VERSION 5.7 ;
  NOWIREEXTENSIONATPIN ON ;
  DIVIDERCHAR "/" ;
  BUSBITCHARS "[]" ;
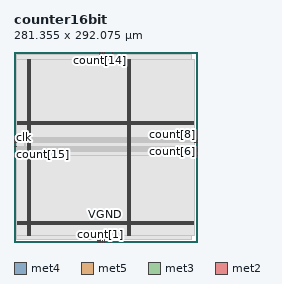
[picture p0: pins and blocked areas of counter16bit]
MACRO counter16bit
  CLASS BLOCK ;
  FOREIGN counter16bit ;
  ORIGIN 0.000 0.000 ;
  SIZE 281.355 BY 292.075 ;
  PIN VGND
    DIRECTION INOUT ;
    USE GROUND ;
    PORT
      LAYER met4 ;
        RECT 24.340 10.640 25.940 280.400 ;
    END
    PORT
      LAYER met4 ;
        RECT 177.940 10.640 179.540 280.400 ;
    END
    PORT
      LAYER met5 ;
        RECT 5.280 30.030 275.780 31.630 ;
    END
    PORT
      LAYER met5 ;
        RECT 5.280 183.210 275.780 184.810 ;
    END
  END VGND
  PIN VPWR
    DIRECTION INOUT ;
    USE POWER ;
    PORT
      LAYER met4 ;
        RECT 21.040 10.640 22.640 280.400 ;
    END
    PORT
      LAYER met4 ;
        RECT 174.640 10.640 176.240 280.400 ;
    END
    PORT
      LAYER met5 ;
        RECT 5.280 26.730 275.780 28.330 ;
    END
    PORT
      LAYER met5 ;
        RECT 5.280 179.910 275.780 181.510 ;
    END
  END VPWR
  PIN clk
    DIRECTION INPUT ;
    USE SIGNAL ;
    ANTENNAGATEAREA 0.852000 ;
    PORT
      LAYER met3 ;
        RECT 0.000 159.840 4.000 160.440 ;
    END
  END clk
  PIN count[0]
    DIRECTION OUTPUT ;
    USE SIGNAL ;
    ANTENNADIFFAREA 0.445500 ;
    PORT
      LAYER met2 ;
        RECT 128.890 0.000 129.170 4.000 ;
    END
  END count[0]
  PIN count[10]
    DIRECTION OUTPUT ;
    USE SIGNAL ;
    ANTENNADIFFAREA 0.795200 ;
    PORT
      LAYER met2 ;
        RECT 151.430 288.075 151.710 292.075 ;
    END
  END count[10]
  PIN count[11]
    DIRECTION OUTPUT ;
    USE SIGNAL ;
    ANTENNADIFFAREA 0.445500 ;
    PORT
      LAYER met3 ;
        RECT 0.000 156.440 4.000 157.040 ;
    END
  END count[11]
  PIN count[12]
    DIRECTION OUTPUT ;
    USE SIGNAL ;
    ANTENNADIFFAREA 0.795200 ;
    PORT
      LAYER met2 ;
        RECT 135.330 288.075 135.610 292.075 ;
    END
  END count[12]
  PIN count[13]
    DIRECTION OUTPUT ;
    USE SIGNAL ;
    ANTENNADIFFAREA 0.795200 ;
    PORT
      LAYER met2 ;
        RECT 138.550 288.075 138.830 292.075 ;
    END
  END count[13]
  PIN count[14]
    DIRECTION OUTPUT ;
    USE SIGNAL ;
    ANTENNADIFFAREA 0.795200 ;
    PORT
      LAYER met2 ;
        RECT 132.110 288.075 132.390 292.075 ;
    END
  END count[14]
  PIN count[15]
    DIRECTION OUTPUT ;
    USE SIGNAL ;
    ANTENNADIFFAREA 0.445500 ;
    PORT
      LAYER met3 ;
        RECT 0.000 146.240 4.000 146.840 ;
    END
  END count[15]
  PIN count[1]
    DIRECTION OUTPUT ;
    USE SIGNAL ;
    ANTENNADIFFAREA 0.445500 ;
    PORT
      LAYER met2 ;
        RECT 132.110 0.000 132.390 4.000 ;
    END
  END count[1]
  PIN count[2]
    DIRECTION OUTPUT ;
    USE SIGNAL ;
    ANTENNADIFFAREA 0.445500 ;
    PORT
      LAYER met2 ;
        RECT 138.550 0.000 138.830 4.000 ;
    END
  END count[2]
  PIN count[3]
    DIRECTION OUTPUT ;
    USE SIGNAL ;
    ANTENNADIFFAREA 0.445500 ;
    PORT
      LAYER met2 ;
        RECT 135.330 0.000 135.610 4.000 ;
    END
  END count[3]
  PIN count[4]
    DIRECTION OUTPUT ;
    USE SIGNAL ;
    ANTENNADIFFAREA 0.445500 ;
    PORT
      LAYER met2 ;
        RECT 148.210 0.000 148.490 4.000 ;
    END
  END count[4]
  PIN count[5]
    DIRECTION OUTPUT ;
    USE SIGNAL ;
    ANTENNADIFFAREA 0.445500 ;
    PORT
      LAYER met3 ;
        RECT 277.355 132.640 281.355 133.240 ;
    END
  END count[5]
  PIN count[6]
    DIRECTION OUTPUT ;
    USE SIGNAL ;
    ANTENNADIFFAREA 0.445500 ;
    PORT
      LAYER met3 ;
        RECT 277.355 139.440 281.355 140.040 ;
    END
  END count[6]
  PIN count[7]
    DIRECTION OUTPUT ;
    USE SIGNAL ;
    ANTENNADIFFAREA 0.445500 ;
    PORT
      LAYER met3 ;
        RECT 277.355 142.840 281.355 143.440 ;
    END
  END count[7]
  PIN count[8]
    DIRECTION OUTPUT ;
    USE SIGNAL ;
    ANTENNADIFFAREA 0.445500 ;
    PORT
      LAYER met3 ;
        RECT 277.355 153.040 281.355 153.640 ;
    END
  END count[8]
  PIN count[9]
    DIRECTION OUTPUT ;
    USE SIGNAL ;
    ANTENNADIFFAREA 0.445500 ;
    PORT
      LAYER met3 ;
        RECT 277.355 156.440 281.355 157.040 ;
    END
  END count[9]
  PIN rst
    DIRECTION INPUT ;
    USE SIGNAL ;
    ANTENNAGATEAREA 0.159000 ;
    PORT
      LAYER met3 ;
        RECT 0.000 153.040 4.000 153.640 ;
    END
  END rst
  OBS
      LAYER nwell ;
        RECT 5.330 10.795 275.730 280.350 ;
      LAYER li1 ;
        RECT 5.520 10.795 275.540 280.245 ;
      LAYER met1 ;
        RECT 4.210 10.640 275.540 280.400 ;
      LAYER met2 ;
        RECT 4.230 287.795 131.830 288.730 ;
        RECT 132.670 287.795 135.050 288.730 ;
        RECT 135.890 287.795 138.270 288.730 ;
        RECT 139.110 287.795 151.150 288.730 ;
        RECT 151.990 287.795 273.610 288.730 ;
        RECT 4.230 4.280 273.610 287.795 ;
        RECT 4.230 4.000 128.610 4.280 ;
        RECT 129.450 4.000 131.830 4.280 ;
        RECT 132.670 4.000 135.050 4.280 ;
        RECT 135.890 4.000 138.270 4.280 ;
        RECT 139.110 4.000 147.930 4.280 ;
        RECT 148.770 4.000 273.610 4.280 ;
      LAYER met3 ;
        RECT 3.990 160.840 277.355 280.325 ;
        RECT 4.400 159.440 277.355 160.840 ;
        RECT 3.990 157.440 277.355 159.440 ;
        RECT 4.400 156.040 276.955 157.440 ;
        RECT 3.990 154.040 277.355 156.040 ;
        RECT 4.400 152.640 276.955 154.040 ;
        RECT 3.990 147.240 277.355 152.640 ;
        RECT 4.400 145.840 277.355 147.240 ;
        RECT 3.990 143.840 277.355 145.840 ;
        RECT 3.990 142.440 276.955 143.840 ;
        RECT 3.990 140.440 277.355 142.440 ;
        RECT 3.990 139.040 276.955 140.440 ;
        RECT 3.990 133.640 277.355 139.040 ;
        RECT 3.990 132.240 276.955 133.640 ;
        RECT 3.990 10.715 277.355 132.240 ;
      LAYER met4 ;
        RECT 16.855 145.695 17.185 160.305 ;
  END
END counter16bit
END LIBRARY

